# Generated by FakeRAM 2.0
VERSION 5.7 ;
BUSBITCHARS "[]" ;
PROPERTYDEFINITIONS
  MACRO width INTEGER ;
  MACRO depth INTEGER ;
  MACRO banks INTEGER ;
END PROPERTYDEFINITIONS
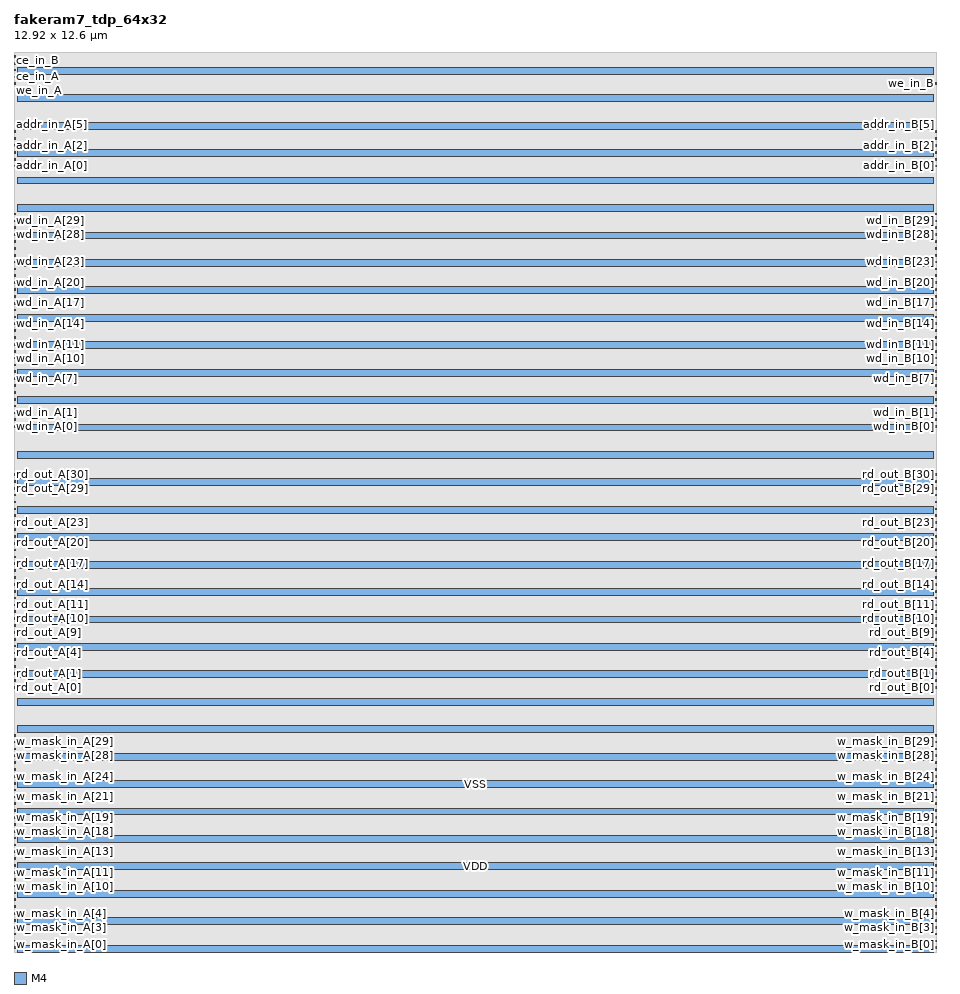
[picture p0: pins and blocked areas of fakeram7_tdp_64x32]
MACRO fakeram7_tdp_64x32
  PROPERTY width 32 ;
  PROPERTY depth 64 ;
  PROPERTY banks 2 ;
  FOREIGN fakeram7_tdp_64x32 0 0 ;
  SYMMETRY X Y ;
  SIZE 12.920 BY 12.600 ;
  CLASS BLOCK ;
  PIN w_mask_in_A[0]
    DIRECTION INPUT ;
    USE SIGNAL ;
    SHAPE ABUTMENT ;
    PORT
      LAYER M4 ;
      RECT 0.000 0.048 0.024 0.072 ;
    END
  END w_mask_in_A[0]
  PIN w_mask_in_B[0]
    DIRECTION INPUT ;
    USE SIGNAL ;
    SHAPE ABUTMENT ;
    PORT
      LAYER M4 ;
      RECT 12.896 0.048 12.920 0.072 ;
    END
  END w_mask_in_B[0]
  PIN w_mask_in_A[1]
    DIRECTION INPUT ;
    USE SIGNAL ;
    SHAPE ABUTMENT ;
    PORT
      LAYER M4 ;
      RECT 0.000 0.144 0.024 0.168 ;
    END
  END w_mask_in_A[1]
  PIN w_mask_in_B[1]
    DIRECTION INPUT ;
    USE SIGNAL ;
    SHAPE ABUTMENT ;
    PORT
      LAYER M4 ;
      RECT 12.896 0.144 12.920 0.168 ;
    END
  END w_mask_in_B[1]
  PIN w_mask_in_A[2]
    DIRECTION INPUT ;
    USE SIGNAL ;
    SHAPE ABUTMENT ;
    PORT
      LAYER M4 ;
      RECT 0.000 0.240 0.024 0.264 ;
    END
  END w_mask_in_A[2]
  PIN w_mask_in_B[2]
    DIRECTION INPUT ;
    USE SIGNAL ;
    SHAPE ABUTMENT ;
    PORT
      LAYER M4 ;
      RECT 12.896 0.240 12.920 0.264 ;
    END
  END w_mask_in_B[2]
  PIN w_mask_in_A[3]
    DIRECTION INPUT ;
    USE SIGNAL ;
    SHAPE ABUTMENT ;
    PORT
      LAYER M4 ;
      RECT 0.000 0.336 0.024 0.360 ;
    END
  END w_mask_in_A[3]
  PIN w_mask_in_B[3]
    DIRECTION INPUT ;
    USE SIGNAL ;
    SHAPE ABUTMENT ;
    PORT
      LAYER M4 ;
      RECT 12.896 0.336 12.920 0.360 ;
    END
  END w_mask_in_B[3]
  PIN w_mask_in_A[4]
    DIRECTION INPUT ;
    USE SIGNAL ;
    SHAPE ABUTMENT ;
    PORT
      LAYER M4 ;
      RECT 0.000 0.432 0.024 0.456 ;
    END
  END w_mask_in_A[4]
  PIN w_mask_in_B[4]
    DIRECTION INPUT ;
    USE SIGNAL ;
    SHAPE ABUTMENT ;
    PORT
      LAYER M4 ;
      RECT 12.896 0.432 12.920 0.456 ;
    END
  END w_mask_in_B[4]
  PIN w_mask_in_A[5]
    DIRECTION INPUT ;
    USE SIGNAL ;
    SHAPE ABUTMENT ;
    PORT
      LAYER M4 ;
      RECT 0.000 0.528 0.024 0.552 ;
    END
  END w_mask_in_A[5]
  PIN w_mask_in_B[5]
    DIRECTION INPUT ;
    USE SIGNAL ;
    SHAPE ABUTMENT ;
    PORT
      LAYER M4 ;
      RECT 12.896 0.528 12.920 0.552 ;
    END
  END w_mask_in_B[5]
  PIN w_mask_in_A[6]
    DIRECTION INPUT ;
    USE SIGNAL ;
    SHAPE ABUTMENT ;
    PORT
      LAYER M4 ;
      RECT 0.000 0.624 0.024 0.648 ;
    END
  END w_mask_in_A[6]
  PIN w_mask_in_B[6]
    DIRECTION INPUT ;
    USE SIGNAL ;
    SHAPE ABUTMENT ;
    PORT
      LAYER M4 ;
      RECT 12.896 0.624 12.920 0.648 ;
    END
  END w_mask_in_B[6]
  PIN w_mask_in_A[7]
    DIRECTION INPUT ;
    USE SIGNAL ;
    SHAPE ABUTMENT ;
    PORT
      LAYER M4 ;
      RECT 0.000 0.720 0.024 0.744 ;
    END
  END w_mask_in_A[7]
  PIN w_mask_in_B[7]
    DIRECTION INPUT ;
    USE SIGNAL ;
    SHAPE ABUTMENT ;
    PORT
      LAYER M4 ;
      RECT 12.896 0.720 12.920 0.744 ;
    END
  END w_mask_in_B[7]
  PIN w_mask_in_A[8]
    DIRECTION INPUT ;
    USE SIGNAL ;
    SHAPE ABUTMENT ;
    PORT
      LAYER M4 ;
      RECT 0.000 0.816 0.024 0.840 ;
    END
  END w_mask_in_A[8]
  PIN w_mask_in_B[8]
    DIRECTION INPUT ;
    USE SIGNAL ;
    SHAPE ABUTMENT ;
    PORT
      LAYER M4 ;
      RECT 12.896 0.816 12.920 0.840 ;
    END
  END w_mask_in_B[8]
  PIN w_mask_in_A[9]
    DIRECTION INPUT ;
    USE SIGNAL ;
    SHAPE ABUTMENT ;
    PORT
      LAYER M4 ;
      RECT 0.000 0.912 0.024 0.936 ;
    END
  END w_mask_in_A[9]
  PIN w_mask_in_B[9]
    DIRECTION INPUT ;
    USE SIGNAL ;
    SHAPE ABUTMENT ;
    PORT
      LAYER M4 ;
      RECT 12.896 0.912 12.920 0.936 ;
    END
  END w_mask_in_B[9]
  PIN w_mask_in_A[10]
    DIRECTION INPUT ;
    USE SIGNAL ;
    SHAPE ABUTMENT ;
    PORT
      LAYER M4 ;
      RECT 0.000 1.008 0.024 1.032 ;
    END
  END w_mask_in_A[10]
  PIN w_mask_in_B[10]
    DIRECTION INPUT ;
    USE SIGNAL ;
    SHAPE ABUTMENT ;
    PORT
      LAYER M4 ;
      RECT 12.896 1.008 12.920 1.032 ;
    END
  END w_mask_in_B[10]
  PIN w_mask_in_A[11]
    DIRECTION INPUT ;
    USE SIGNAL ;
    SHAPE ABUTMENT ;
    PORT
      LAYER M4 ;
      RECT 0.000 1.104 0.024 1.128 ;
    END
  END w_mask_in_A[11]
  PIN w_mask_in_B[11]
    DIRECTION INPUT ;
    USE SIGNAL ;
    SHAPE ABUTMENT ;
    PORT
      LAYER M4 ;
      RECT 12.896 1.104 12.920 1.128 ;
    END
  END w_mask_in_B[11]
  PIN w_mask_in_A[12]
    DIRECTION INPUT ;
    USE SIGNAL ;
    SHAPE ABUTMENT ;
    PORT
      LAYER M4 ;
      RECT 0.000 1.200 0.024 1.224 ;
    END
  END w_mask_in_A[12]
  PIN w_mask_in_B[12]
    DIRECTION INPUT ;
    USE SIGNAL ;
    SHAPE ABUTMENT ;
    PORT
      LAYER M4 ;
      RECT 12.896 1.200 12.920 1.224 ;
    END
  END w_mask_in_B[12]
  PIN w_mask_in_A[13]
    DIRECTION INPUT ;
    USE SIGNAL ;
    SHAPE ABUTMENT ;
    PORT
      LAYER M4 ;
      RECT 0.000 1.296 0.024 1.320 ;
    END
  END w_mask_in_A[13]
  PIN w_mask_in_B[13]
    DIRECTION INPUT ;
    USE SIGNAL ;
    SHAPE ABUTMENT ;
    PORT
      LAYER M4 ;
      RECT 12.896 1.296 12.920 1.320 ;
    END
  END w_mask_in_B[13]
  PIN w_mask_in_A[14]
    DIRECTION INPUT ;
    USE SIGNAL ;
    SHAPE ABUTMENT ;
    PORT
      LAYER M4 ;
      RECT 0.000 1.392 0.024 1.416 ;
    END
  END w_mask_in_A[14]
  PIN w_mask_in_B[14]
    DIRECTION INPUT ;
    USE SIGNAL ;
    SHAPE ABUTMENT ;
    PORT
      LAYER M4 ;
      RECT 12.896 1.392 12.920 1.416 ;
    END
  END w_mask_in_B[14]
  PIN w_mask_in_A[15]
    DIRECTION INPUT ;
    USE SIGNAL ;
    SHAPE ABUTMENT ;
    PORT
      LAYER M4 ;
      RECT 0.000 1.488 0.024 1.512 ;
    END
  END w_mask_in_A[15]
  PIN w_mask_in_B[15]
    DIRECTION INPUT ;
    USE SIGNAL ;
    SHAPE ABUTMENT ;
    PORT
      LAYER M4 ;
      RECT 12.896 1.488 12.920 1.512 ;
    END
  END w_mask_in_B[15]
  PIN w_mask_in_A[16]
    DIRECTION INPUT ;
    USE SIGNAL ;
    SHAPE ABUTMENT ;
    PORT
      LAYER M4 ;
      RECT 0.000 1.584 0.024 1.608 ;
    END
  END w_mask_in_A[16]
  PIN w_mask_in_B[16]
    DIRECTION INPUT ;
    USE SIGNAL ;
    SHAPE ABUTMENT ;
    PORT
      LAYER M4 ;
      RECT 12.896 1.584 12.920 1.608 ;
    END
  END w_mask_in_B[16]
  PIN w_mask_in_A[17]
    DIRECTION INPUT ;
    USE SIGNAL ;
    SHAPE ABUTMENT ;
    PORT
      LAYER M4 ;
      RECT 0.000 1.680 0.024 1.704 ;
    END
  END w_mask_in_A[17]
  PIN w_mask_in_B[17]
    DIRECTION INPUT ;
    USE SIGNAL ;
    SHAPE ABUTMENT ;
    PORT
      LAYER M4 ;
      RECT 12.896 1.680 12.920 1.704 ;
    END
  END w_mask_in_B[17]
  PIN w_mask_in_A[18]
    DIRECTION INPUT ;
    USE SIGNAL ;
    SHAPE ABUTMENT ;
    PORT
      LAYER M4 ;
      RECT 0.000 1.776 0.024 1.800 ;
    END
  END w_mask_in_A[18]
  PIN w_mask_in_B[18]
    DIRECTION INPUT ;
    USE SIGNAL ;
    SHAPE ABUTMENT ;
    PORT
      LAYER M4 ;
      RECT 12.896 1.776 12.920 1.800 ;
    END
  END w_mask_in_B[18]
  PIN w_mask_in_A[19]
    DIRECTION INPUT ;
    USE SIGNAL ;
    SHAPE ABUTMENT ;
    PORT
      LAYER M4 ;
      RECT 0.000 1.872 0.024 1.896 ;
    END
  END w_mask_in_A[19]
  PIN w_mask_in_B[19]
    DIRECTION INPUT ;
    USE SIGNAL ;
    SHAPE ABUTMENT ;
    PORT
      LAYER M4 ;
      RECT 12.896 1.872 12.920 1.896 ;
    END
  END w_mask_in_B[19]
  PIN w_mask_in_A[20]
    DIRECTION INPUT ;
    USE SIGNAL ;
    SHAPE ABUTMENT ;
    PORT
      LAYER M4 ;
      RECT 0.000 1.968 0.024 1.992 ;
    END
  END w_mask_in_A[20]
  PIN w_mask_in_B[20]
    DIRECTION INPUT ;
    USE SIGNAL ;
    SHAPE ABUTMENT ;
    PORT
      LAYER M4 ;
      RECT 12.896 1.968 12.920 1.992 ;
    END
  END w_mask_in_B[20]
  PIN w_mask_in_A[21]
    DIRECTION INPUT ;
    USE SIGNAL ;
    SHAPE ABUTMENT ;
    PORT
      LAYER M4 ;
      RECT 0.000 2.064 0.024 2.088 ;
    END
  END w_mask_in_A[21]
  PIN w_mask_in_B[21]
    DIRECTION INPUT ;
    USE SIGNAL ;
    SHAPE ABUTMENT ;
    PORT
      LAYER M4 ;
      RECT 12.896 2.064 12.920 2.088 ;
    END
  END w_mask_in_B[21]
  PIN w_mask_in_A[22]
    DIRECTION INPUT ;
    USE SIGNAL ;
    SHAPE ABUTMENT ;
    PORT
      LAYER M4 ;
      RECT 0.000 2.160 0.024 2.184 ;
    END
  END w_mask_in_A[22]
  PIN w_mask_in_B[22]
    DIRECTION INPUT ;
    USE SIGNAL ;
    SHAPE ABUTMENT ;
    PORT
      LAYER M4 ;
      RECT 12.896 2.160 12.920 2.184 ;
    END
  END w_mask_in_B[22]
  PIN w_mask_in_A[23]
    DIRECTION INPUT ;
    USE SIGNAL ;
    SHAPE ABUTMENT ;
    PORT
      LAYER M4 ;
      RECT 0.000 2.256 0.024 2.280 ;
    END
  END w_mask_in_A[23]
  PIN w_mask_in_B[23]
    DIRECTION INPUT ;
    USE SIGNAL ;
    SHAPE ABUTMENT ;
    PORT
      LAYER M4 ;
      RECT 12.896 2.256 12.920 2.280 ;
    END
  END w_mask_in_B[23]
  PIN w_mask_in_A[24]
    DIRECTION INPUT ;
    USE SIGNAL ;
    SHAPE ABUTMENT ;
    PORT
      LAYER M4 ;
      RECT 0.000 2.352 0.024 2.376 ;
    END
  END w_mask_in_A[24]
  PIN w_mask_in_B[24]
    DIRECTION INPUT ;
    USE SIGNAL ;
    SHAPE ABUTMENT ;
    PORT
      LAYER M4 ;
      RECT 12.896 2.352 12.920 2.376 ;
    END
  END w_mask_in_B[24]
  PIN w_mask_in_A[25]
    DIRECTION INPUT ;
    USE SIGNAL ;
    SHAPE ABUTMENT ;
    PORT
      LAYER M4 ;
      RECT 0.000 2.448 0.024 2.472 ;
    END
  END w_mask_in_A[25]
  PIN w_mask_in_B[25]
    DIRECTION INPUT ;
    USE SIGNAL ;
    SHAPE ABUTMENT ;
    PORT
      LAYER M4 ;
      RECT 12.896 2.448 12.920 2.472 ;
    END
  END w_mask_in_B[25]
  PIN w_mask_in_A[26]
    DIRECTION INPUT ;
    USE SIGNAL ;
    SHAPE ABUTMENT ;
    PORT
      LAYER M4 ;
      RECT 0.000 2.544 0.024 2.568 ;
    END
  END w_mask_in_A[26]
  PIN w_mask_in_B[26]
    DIRECTION INPUT ;
    USE SIGNAL ;
    SHAPE ABUTMENT ;
    PORT
      LAYER M4 ;
      RECT 12.896 2.544 12.920 2.568 ;
    END
  END w_mask_in_B[26]
  PIN w_mask_in_A[27]
    DIRECTION INPUT ;
    USE SIGNAL ;
    SHAPE ABUTMENT ;
    PORT
      LAYER M4 ;
      RECT 0.000 2.640 0.024 2.664 ;
    END
  END w_mask_in_A[27]
  PIN w_mask_in_B[27]
    DIRECTION INPUT ;
    USE SIGNAL ;
    SHAPE ABUTMENT ;
    PORT
      LAYER M4 ;
      RECT 12.896 2.640 12.920 2.664 ;
    END
  END w_mask_in_B[27]
  PIN w_mask_in_A[28]
    DIRECTION INPUT ;
    USE SIGNAL ;
    SHAPE ABUTMENT ;
    PORT
      LAYER M4 ;
      RECT 0.000 2.736 0.024 2.760 ;
    END
  END w_mask_in_A[28]
  PIN w_mask_in_B[28]
    DIRECTION INPUT ;
    USE SIGNAL ;
    SHAPE ABUTMENT ;
    PORT
      LAYER M4 ;
      RECT 12.896 2.736 12.920 2.760 ;
    END
  END w_mask_in_B[28]
  PIN w_mask_in_A[29]
    DIRECTION INPUT ;
    USE SIGNAL ;
    SHAPE ABUTMENT ;
    PORT
      LAYER M4 ;
      RECT 0.000 2.832 0.024 2.856 ;
    END
  END w_mask_in_A[29]
  PIN w_mask_in_B[29]
    DIRECTION INPUT ;
    USE SIGNAL ;
    SHAPE ABUTMENT ;
    PORT
      LAYER M4 ;
      RECT 12.896 2.832 12.920 2.856 ;
    END
  END w_mask_in_B[29]
  PIN w_mask_in_A[30]
    DIRECTION INPUT ;
    USE SIGNAL ;
    SHAPE ABUTMENT ;
    PORT
      LAYER M4 ;
      RECT 0.000 2.928 0.024 2.952 ;
    END
  END w_mask_in_A[30]
  PIN w_mask_in_B[30]
    DIRECTION INPUT ;
    USE SIGNAL ;
    SHAPE ABUTMENT ;
    PORT
      LAYER M4 ;
      RECT 12.896 2.928 12.920 2.952 ;
    END
  END w_mask_in_B[30]
  PIN w_mask_in_A[31]
    DIRECTION INPUT ;
    USE SIGNAL ;
    SHAPE ABUTMENT ;
    PORT
      LAYER M4 ;
      RECT 0.000 3.024 0.024 3.048 ;
    END
  END w_mask_in_A[31]
  PIN w_mask_in_B[31]
    DIRECTION INPUT ;
    USE SIGNAL ;
    SHAPE ABUTMENT ;
    PORT
      LAYER M4 ;
      RECT 12.896 3.024 12.920 3.048 ;
    END
  END w_mask_in_B[31]
  PIN rd_out_A[0]
    DIRECTION OUTPUT ;
    USE SIGNAL ;
    SHAPE ABUTMENT ;
    PORT
      LAYER M4 ;
      RECT 0.000 3.696 0.024 3.720 ;
    END
  END rd_out_A[0]
  PIN rd_out_B[0]
    DIRECTION OUTPUT ;
    USE SIGNAL ;
    SHAPE ABUTMENT ;
    PORT
      LAYER M4 ;
      RECT 12.896 3.696 12.920 3.720 ;
    END
  END rd_out_B[0]
  PIN rd_out_A[1]
    DIRECTION OUTPUT ;
    USE SIGNAL ;
    SHAPE ABUTMENT ;
    PORT
      LAYER M4 ;
      RECT 0.000 3.792 0.024 3.816 ;
    END
  END rd_out_A[1]
  PIN rd_out_B[1]
    DIRECTION OUTPUT ;
    USE SIGNAL ;
    SHAPE ABUTMENT ;
    PORT
      LAYER M4 ;
      RECT 12.896 3.792 12.920 3.816 ;
    END
  END rd_out_B[1]
  PIN rd_out_A[2]
    DIRECTION OUTPUT ;
    USE SIGNAL ;
    SHAPE ABUTMENT ;
    PORT
      LAYER M4 ;
      RECT 0.000 3.888 0.024 3.912 ;
    END
  END rd_out_A[2]
  PIN rd_out_B[2]
    DIRECTION OUTPUT ;
    USE SIGNAL ;
    SHAPE ABUTMENT ;
    PORT
      LAYER M4 ;
      RECT 12.896 3.888 12.920 3.912 ;
    END
  END rd_out_B[2]
  PIN rd_out_A[3]
    DIRECTION OUTPUT ;
    USE SIGNAL ;
    SHAPE ABUTMENT ;
    PORT
      LAYER M4 ;
      RECT 0.000 3.984 0.024 4.008 ;
    END
  END rd_out_A[3]
  PIN rd_out_B[3]
    DIRECTION OUTPUT ;
    USE SIGNAL ;
    SHAPE ABUTMENT ;
    PORT
      LAYER M4 ;
      RECT 12.896 3.984 12.920 4.008 ;
    END
  END rd_out_B[3]
  PIN rd_out_A[4]
    DIRECTION OUTPUT ;
    USE SIGNAL ;
    SHAPE ABUTMENT ;
    PORT
      LAYER M4 ;
      RECT 0.000 4.080 0.024 4.104 ;
    END
  END rd_out_A[4]
  PIN rd_out_B[4]
    DIRECTION OUTPUT ;
    USE SIGNAL ;
    SHAPE ABUTMENT ;
    PORT
      LAYER M4 ;
      RECT 12.896 4.080 12.920 4.104 ;
    END
  END rd_out_B[4]
  PIN rd_out_A[5]
    DIRECTION OUTPUT ;
    USE SIGNAL ;
    SHAPE ABUTMENT ;
    PORT
      LAYER M4 ;
      RECT 0.000 4.176 0.024 4.200 ;
    END
  END rd_out_A[5]
  PIN rd_out_B[5]
    DIRECTION OUTPUT ;
    USE SIGNAL ;
    SHAPE ABUTMENT ;
    PORT
      LAYER M4 ;
      RECT 12.896 4.176 12.920 4.200 ;
    END
  END rd_out_B[5]
  PIN rd_out_A[6]
    DIRECTION OUTPUT ;
    USE SIGNAL ;
    SHAPE ABUTMENT ;
    PORT
      LAYER M4 ;
      RECT 0.000 4.272 0.024 4.296 ;
    END
  END rd_out_A[6]
  PIN rd_out_B[6]
    DIRECTION OUTPUT ;
    USE SIGNAL ;
    SHAPE ABUTMENT ;
    PORT
      LAYER M4 ;
      RECT 12.896 4.272 12.920 4.296 ;
    END
  END rd_out_B[6]
  PIN rd_out_A[7]
    DIRECTION OUTPUT ;
    USE SIGNAL ;
    SHAPE ABUTMENT ;
    PORT
      LAYER M4 ;
      RECT 0.000 4.368 0.024 4.392 ;
    END
  END rd_out_A[7]
  PIN rd_out_B[7]
    DIRECTION OUTPUT ;
    USE SIGNAL ;
    SHAPE ABUTMENT ;
    PORT
      LAYER M4 ;
      RECT 12.896 4.368 12.920 4.392 ;
    END
  END rd_out_B[7]
  PIN rd_out_A[8]
    DIRECTION OUTPUT ;
    USE SIGNAL ;
    SHAPE ABUTMENT ;
    PORT
      LAYER M4 ;
      RECT 0.000 4.464 0.024 4.488 ;
    END
  END rd_out_A[8]
  PIN rd_out_B[8]
    DIRECTION OUTPUT ;
    USE SIGNAL ;
    SHAPE ABUTMENT ;
    PORT
      LAYER M4 ;
      RECT 12.896 4.464 12.920 4.488 ;
    END
  END rd_out_B[8]
  PIN rd_out_A[9]
    DIRECTION OUTPUT ;
    USE SIGNAL ;
    SHAPE ABUTMENT ;
    PORT
      LAYER M4 ;
      RECT 0.000 4.560 0.024 4.584 ;
    END
  END rd_out_A[9]
  PIN rd_out_B[9]
    DIRECTION OUTPUT ;
    USE SIGNAL ;
    SHAPE ABUTMENT ;
    PORT
      LAYER M4 ;
      RECT 12.896 4.560 12.920 4.584 ;
    END
  END rd_out_B[9]
  PIN rd_out_A[10]
    DIRECTION OUTPUT ;
    USE SIGNAL ;
    SHAPE ABUTMENT ;
    PORT
      LAYER M4 ;
      RECT 0.000 4.656 0.024 4.680 ;
    END
  END rd_out_A[10]
  PIN rd_out_B[10]
    DIRECTION OUTPUT ;
    USE SIGNAL ;
    SHAPE ABUTMENT ;
    PORT
      LAYER M4 ;
      RECT 12.896 4.656 12.920 4.680 ;
    END
  END rd_out_B[10]
  PIN rd_out_A[11]
    DIRECTION OUTPUT ;
    USE SIGNAL ;
    SHAPE ABUTMENT ;
    PORT
      LAYER M4 ;
      RECT 0.000 4.752 0.024 4.776 ;
    END
  END rd_out_A[11]
  PIN rd_out_B[11]
    DIRECTION OUTPUT ;
    USE SIGNAL ;
    SHAPE ABUTMENT ;
    PORT
      LAYER M4 ;
      RECT 12.896 4.752 12.920 4.776 ;
    END
  END rd_out_B[11]
  PIN rd_out_A[12]
    DIRECTION OUTPUT ;
    USE SIGNAL ;
    SHAPE ABUTMENT ;
    PORT
      LAYER M4 ;
      RECT 0.000 4.848 0.024 4.872 ;
    END
  END rd_out_A[12]
  PIN rd_out_B[12]
    DIRECTION OUTPUT ;
    USE SIGNAL ;
    SHAPE ABUTMENT ;
    PORT
      LAYER M4 ;
      RECT 12.896 4.848 12.920 4.872 ;
    END
  END rd_out_B[12]
  PIN rd_out_A[13]
    DIRECTION OUTPUT ;
    USE SIGNAL ;
    SHAPE ABUTMENT ;
    PORT
      LAYER M4 ;
      RECT 0.000 4.944 0.024 4.968 ;
    END
  END rd_out_A[13]
  PIN rd_out_B[13]
    DIRECTION OUTPUT ;
    USE SIGNAL ;
    SHAPE ABUTMENT ;
    PORT
      LAYER M4 ;
      RECT 12.896 4.944 12.920 4.968 ;
    END
  END rd_out_B[13]
  PIN rd_out_A[14]
    DIRECTION OUTPUT ;
    USE SIGNAL ;
    SHAPE ABUTMENT ;
    PORT
      LAYER M4 ;
      RECT 0.000 5.040 0.024 5.064 ;
    END
  END rd_out_A[14]
  PIN rd_out_B[14]
    DIRECTION OUTPUT ;
    USE SIGNAL ;
    SHAPE ABUTMENT ;
    PORT
      LAYER M4 ;
      RECT 12.896 5.040 12.920 5.064 ;
    END
  END rd_out_B[14]
  PIN rd_out_A[15]
    DIRECTION OUTPUT ;
    USE SIGNAL ;
    SHAPE ABUTMENT ;
    PORT
      LAYER M4 ;
      RECT 0.000 5.136 0.024 5.160 ;
    END
  END rd_out_A[15]
  PIN rd_out_B[15]
    DIRECTION OUTPUT ;
    USE SIGNAL ;
    SHAPE ABUTMENT ;
    PORT
      LAYER M4 ;
      RECT 12.896 5.136 12.920 5.160 ;
    END
  END rd_out_B[15]
  PIN rd_out_A[16]
    DIRECTION OUTPUT ;
    USE SIGNAL ;
    SHAPE ABUTMENT ;
    PORT
      LAYER M4 ;
      RECT 0.000 5.232 0.024 5.256 ;
    END
  END rd_out_A[16]
  PIN rd_out_B[16]
    DIRECTION OUTPUT ;
    USE SIGNAL ;
    SHAPE ABUTMENT ;
    PORT
      LAYER M4 ;
      RECT 12.896 5.232 12.920 5.256 ;
    END
  END rd_out_B[16]
  PIN rd_out_A[17]
    DIRECTION OUTPUT ;
    USE SIGNAL ;
    SHAPE ABUTMENT ;
    PORT
      LAYER M4 ;
      RECT 0.000 5.328 0.024 5.352 ;
    END
  END rd_out_A[17]
  PIN rd_out_B[17]
    DIRECTION OUTPUT ;
    USE SIGNAL ;
    SHAPE ABUTMENT ;
    PORT
      LAYER M4 ;
      RECT 12.896 5.328 12.920 5.352 ;
    END
  END rd_out_B[17]
  PIN rd_out_A[18]
    DIRECTION OUTPUT ;
    USE SIGNAL ;
    SHAPE ABUTMENT ;
    PORT
      LAYER M4 ;
      RECT 0.000 5.424 0.024 5.448 ;
    END
  END rd_out_A[18]
  PIN rd_out_B[18]
    DIRECTION OUTPUT ;
    USE SIGNAL ;
    SHAPE ABUTMENT ;
    PORT
      LAYER M4 ;
      RECT 12.896 5.424 12.920 5.448 ;
    END
  END rd_out_B[18]
  PIN rd_out_A[19]
    DIRECTION OUTPUT ;
    USE SIGNAL ;
    SHAPE ABUTMENT ;
    PORT
      LAYER M4 ;
      RECT 0.000 5.520 0.024 5.544 ;
    END
  END rd_out_A[19]
  PIN rd_out_B[19]
    DIRECTION OUTPUT ;
    USE SIGNAL ;
    SHAPE ABUTMENT ;
    PORT
      LAYER M4 ;
      RECT 12.896 5.520 12.920 5.544 ;
    END
  END rd_out_B[19]
  PIN rd_out_A[20]
    DIRECTION OUTPUT ;
    USE SIGNAL ;
    SHAPE ABUTMENT ;
    PORT
      LAYER M4 ;
      RECT 0.000 5.616 0.024 5.640 ;
    END
  END rd_out_A[20]
  PIN rd_out_B[20]
    DIRECTION OUTPUT ;
    USE SIGNAL ;
    SHAPE ABUTMENT ;
    PORT
      LAYER M4 ;
      RECT 12.896 5.616 12.920 5.640 ;
    END
  END rd_out_B[20]
  PIN rd_out_A[21]
    DIRECTION OUTPUT ;
    USE SIGNAL ;
    SHAPE ABUTMENT ;
    PORT
      LAYER M4 ;
      RECT 0.000 5.712 0.024 5.736 ;
    END
  END rd_out_A[21]
  PIN rd_out_B[21]
    DIRECTION OUTPUT ;
    USE SIGNAL ;
    SHAPE ABUTMENT ;
    PORT
      LAYER M4 ;
      RECT 12.896 5.712 12.920 5.736 ;
    END
  END rd_out_B[21]
  PIN rd_out_A[22]
    DIRECTION OUTPUT ;
    USE SIGNAL ;
    SHAPE ABUTMENT ;
    PORT
      LAYER M4 ;
      RECT 0.000 5.808 0.024 5.832 ;
    END
  END rd_out_A[22]
  PIN rd_out_B[22]
    DIRECTION OUTPUT ;
    USE SIGNAL ;
    SHAPE ABUTMENT ;
    PORT
      LAYER M4 ;
      RECT 12.896 5.808 12.920 5.832 ;
    END
  END rd_out_B[22]
  PIN rd_out_A[23]
    DIRECTION OUTPUT ;
    USE SIGNAL ;
    SHAPE ABUTMENT ;
    PORT
      LAYER M4 ;
      RECT 0.000 5.904 0.024 5.928 ;
    END
  END rd_out_A[23]
  PIN rd_out_B[23]
    DIRECTION OUTPUT ;
    USE SIGNAL ;
    SHAPE ABUTMENT ;
    PORT
      LAYER M4 ;
      RECT 12.896 5.904 12.920 5.928 ;
    END
  END rd_out_B[23]
  PIN rd_out_A[24]
    DIRECTION OUTPUT ;
    USE SIGNAL ;
    SHAPE ABUTMENT ;
    PORT
      LAYER M4 ;
      RECT 0.000 6.000 0.024 6.024 ;
    END
  END rd_out_A[24]
  PIN rd_out_B[24]
    DIRECTION OUTPUT ;
    USE SIGNAL ;
    SHAPE ABUTMENT ;
    PORT
      LAYER M4 ;
      RECT 12.896 6.000 12.920 6.024 ;
    END
  END rd_out_B[24]
  PIN rd_out_A[25]
    DIRECTION OUTPUT ;
    USE SIGNAL ;
    SHAPE ABUTMENT ;
    PORT
      LAYER M4 ;
      RECT 0.000 6.096 0.024 6.120 ;
    END
  END rd_out_A[25]
  PIN rd_out_B[25]
    DIRECTION OUTPUT ;
    USE SIGNAL ;
    SHAPE ABUTMENT ;
    PORT
      LAYER M4 ;
      RECT 12.896 6.096 12.920 6.120 ;
    END
  END rd_out_B[25]
  PIN rd_out_A[26]
    DIRECTION OUTPUT ;
    USE SIGNAL ;
    SHAPE ABUTMENT ;
    PORT
      LAYER M4 ;
      RECT 0.000 6.192 0.024 6.216 ;
    END
  END rd_out_A[26]
  PIN rd_out_B[26]
    DIRECTION OUTPUT ;
    USE SIGNAL ;
    SHAPE ABUTMENT ;
    PORT
      LAYER M4 ;
      RECT 12.896 6.192 12.920 6.216 ;
    END
  END rd_out_B[26]
  PIN rd_out_A[27]
    DIRECTION OUTPUT ;
    USE SIGNAL ;
    SHAPE ABUTMENT ;
    PORT
      LAYER M4 ;
      RECT 0.000 6.288 0.024 6.312 ;
    END
  END rd_out_A[27]
  PIN rd_out_B[27]
    DIRECTION OUTPUT ;
    USE SIGNAL ;
    SHAPE ABUTMENT ;
    PORT
      LAYER M4 ;
      RECT 12.896 6.288 12.920 6.312 ;
    END
  END rd_out_B[27]
  PIN rd_out_A[28]
    DIRECTION OUTPUT ;
    USE SIGNAL ;
    SHAPE ABUTMENT ;
    PORT
      LAYER M4 ;
      RECT 0.000 6.384 0.024 6.408 ;
    END
  END rd_out_A[28]
  PIN rd_out_B[28]
    DIRECTION OUTPUT ;
    USE SIGNAL ;
    SHAPE ABUTMENT ;
    PORT
      LAYER M4 ;
      RECT 12.896 6.384 12.920 6.408 ;
    END
  END rd_out_B[28]
  PIN rd_out_A[29]
    DIRECTION OUTPUT ;
    USE SIGNAL ;
    SHAPE ABUTMENT ;
    PORT
      LAYER M4 ;
      RECT 0.000 6.480 0.024 6.504 ;
    END
  END rd_out_A[29]
  PIN rd_out_B[29]
    DIRECTION OUTPUT ;
    USE SIGNAL ;
    SHAPE ABUTMENT ;
    PORT
      LAYER M4 ;
      RECT 12.896 6.480 12.920 6.504 ;
    END
  END rd_out_B[29]
  PIN rd_out_A[30]
    DIRECTION OUTPUT ;
    USE SIGNAL ;
    SHAPE ABUTMENT ;
    PORT
      LAYER M4 ;
      RECT 0.000 6.576 0.024 6.600 ;
    END
  END rd_out_A[30]
  PIN rd_out_B[30]
    DIRECTION OUTPUT ;
    USE SIGNAL ;
    SHAPE ABUTMENT ;
    PORT
      LAYER M4 ;
      RECT 12.896 6.576 12.920 6.600 ;
    END
  END rd_out_B[30]
  PIN rd_out_A[31]
    DIRECTION OUTPUT ;
    USE SIGNAL ;
    SHAPE ABUTMENT ;
    PORT
      LAYER M4 ;
      RECT 0.000 6.672 0.024 6.696 ;
    END
  END rd_out_A[31]
  PIN rd_out_B[31]
    DIRECTION OUTPUT ;
    USE SIGNAL ;
    SHAPE ABUTMENT ;
    PORT
      LAYER M4 ;
      RECT 12.896 6.672 12.920 6.696 ;
    END
  END rd_out_B[31]
  PIN wd_in_A[0]
    DIRECTION INPUT ;
    USE SIGNAL ;
    SHAPE ABUTMENT ;
    PORT
      LAYER M4 ;
      RECT 0.000 7.344 0.024 7.368 ;
    END
  END wd_in_A[0]
  PIN wd_in_B[0]
    DIRECTION INPUT ;
    USE SIGNAL ;
    SHAPE ABUTMENT ;
    PORT
      LAYER M4 ;
      RECT 12.896 7.344 12.920 7.368 ;
    END
  END wd_in_B[0]
  PIN wd_in_A[1]
    DIRECTION INPUT ;
    USE SIGNAL ;
    SHAPE ABUTMENT ;
    PORT
      LAYER M4 ;
      RECT 0.000 7.440 0.024 7.464 ;
    END
  END wd_in_A[1]
  PIN wd_in_B[1]
    DIRECTION INPUT ;
    USE SIGNAL ;
    SHAPE ABUTMENT ;
    PORT
      LAYER M4 ;
      RECT 12.896 7.440 12.920 7.464 ;
    END
  END wd_in_B[1]
  PIN wd_in_A[2]
    DIRECTION INPUT ;
    USE SIGNAL ;
    SHAPE ABUTMENT ;
    PORT
      LAYER M4 ;
      RECT 0.000 7.536 0.024 7.560 ;
    END
  END wd_in_A[2]
  PIN wd_in_B[2]
    DIRECTION INPUT ;
    USE SIGNAL ;
    SHAPE ABUTMENT ;
    PORT
      LAYER M4 ;
      RECT 12.896 7.536 12.920 7.560 ;
    END
  END wd_in_B[2]
  PIN wd_in_A[3]
    DIRECTION INPUT ;
    USE SIGNAL ;
    SHAPE ABUTMENT ;
    PORT
      LAYER M4 ;
      RECT 0.000 7.632 0.024 7.656 ;
    END
  END wd_in_A[3]
  PIN wd_in_B[3]
    DIRECTION INPUT ;
    USE SIGNAL ;
    SHAPE ABUTMENT ;
    PORT
      LAYER M4 ;
      RECT 12.896 7.632 12.920 7.656 ;
    END
  END wd_in_B[3]
  PIN wd_in_A[4]
    DIRECTION INPUT ;
    USE SIGNAL ;
    SHAPE ABUTMENT ;
    PORT
      LAYER M4 ;
      RECT 0.000 7.728 0.024 7.752 ;
    END
  END wd_in_A[4]
  PIN wd_in_B[4]
    DIRECTION INPUT ;
    USE SIGNAL ;
    SHAPE ABUTMENT ;
    PORT
      LAYER M4 ;
      RECT 12.896 7.728 12.920 7.752 ;
    END
  END wd_in_B[4]
  PIN wd_in_A[5]
    DIRECTION INPUT ;
    USE SIGNAL ;
    SHAPE ABUTMENT ;
    PORT
      LAYER M4 ;
      RECT 0.000 7.824 0.024 7.848 ;
    END
  END wd_in_A[5]
  PIN wd_in_B[5]
    DIRECTION INPUT ;
    USE SIGNAL ;
    SHAPE ABUTMENT ;
    PORT
      LAYER M4 ;
      RECT 12.896 7.824 12.920 7.848 ;
    END
  END wd_in_B[5]
  PIN wd_in_A[6]
    DIRECTION INPUT ;
    USE SIGNAL ;
    SHAPE ABUTMENT ;
    PORT
      LAYER M4 ;
      RECT 0.000 7.920 0.024 7.944 ;
    END
  END wd_in_A[6]
  PIN wd_in_B[6]
    DIRECTION INPUT ;
    USE SIGNAL ;
    SHAPE ABUTMENT ;
    PORT
      LAYER M4 ;
      RECT 12.896 7.920 12.920 7.944 ;
    END
  END wd_in_B[6]
  PIN wd_in_A[7]
    DIRECTION INPUT ;
    USE SIGNAL ;
    SHAPE ABUTMENT ;
    PORT
      LAYER M4 ;
      RECT 0.000 8.016 0.024 8.040 ;
    END
  END wd_in_A[7]
  PIN wd_in_B[7]
    DIRECTION INPUT ;
    USE SIGNAL ;
    SHAPE ABUTMENT ;
    PORT
      LAYER M4 ;
      RECT 12.896 8.016 12.920 8.040 ;
    END
  END wd_in_B[7]
  PIN wd_in_A[8]
    DIRECTION INPUT ;
    USE SIGNAL ;
    SHAPE ABUTMENT ;
    PORT
      LAYER M4 ;
      RECT 0.000 8.112 0.024 8.136 ;
    END
  END wd_in_A[8]
  PIN wd_in_B[8]
    DIRECTION INPUT ;
    USE SIGNAL ;
    SHAPE ABUTMENT ;
    PORT
      LAYER M4 ;
      RECT 12.896 8.112 12.920 8.136 ;
    END
  END wd_in_B[8]
  PIN wd_in_A[9]
    DIRECTION INPUT ;
    USE SIGNAL ;
    SHAPE ABUTMENT ;
    PORT
      LAYER M4 ;
      RECT 0.000 8.208 0.024 8.232 ;
    END
  END wd_in_A[9]
  PIN wd_in_B[9]
    DIRECTION INPUT ;
    USE SIGNAL ;
    SHAPE ABUTMENT ;
    PORT
      LAYER M4 ;
      RECT 12.896 8.208 12.920 8.232 ;
    END
  END wd_in_B[9]
  PIN wd_in_A[10]
    DIRECTION INPUT ;
    USE SIGNAL ;
    SHAPE ABUTMENT ;
    PORT
      LAYER M4 ;
      RECT 0.000 8.304 0.024 8.328 ;
    END
  END wd_in_A[10]
  PIN wd_in_B[10]
    DIRECTION INPUT ;
    USE SIGNAL ;
    SHAPE ABUTMENT ;
    PORT
      LAYER M4 ;
      RECT 12.896 8.304 12.920 8.328 ;
    END
  END wd_in_B[10]
  PIN wd_in_A[11]
    DIRECTION INPUT ;
    USE SIGNAL ;
    SHAPE ABUTMENT ;
    PORT
      LAYER M4 ;
      RECT 0.000 8.400 0.024 8.424 ;
    END
  END wd_in_A[11]
  PIN wd_in_B[11]
    DIRECTION INPUT ;
    USE SIGNAL ;
    SHAPE ABUTMENT ;
    PORT
      LAYER M4 ;
      RECT 12.896 8.400 12.920 8.424 ;
    END
  END wd_in_B[11]
  PIN wd_in_A[12]
    DIRECTION INPUT ;
    USE SIGNAL ;
    SHAPE ABUTMENT ;
    PORT
      LAYER M4 ;
      RECT 0.000 8.496 0.024 8.520 ;
    END
  END wd_in_A[12]
  PIN wd_in_B[12]
    DIRECTION INPUT ;
    USE SIGNAL ;
    SHAPE ABUTMENT ;
    PORT
      LAYER M4 ;
      RECT 12.896 8.496 12.920 8.520 ;
    END
  END wd_in_B[12]
  PIN wd_in_A[13]
    DIRECTION INPUT ;
    USE SIGNAL ;
    SHAPE ABUTMENT ;
    PORT
      LAYER M4 ;
      RECT 0.000 8.592 0.024 8.616 ;
    END
  END wd_in_A[13]
  PIN wd_in_B[13]
    DIRECTION INPUT ;
    USE SIGNAL ;
    SHAPE ABUTMENT ;
    PORT
      LAYER M4 ;
      RECT 12.896 8.592 12.920 8.616 ;
    END
  END wd_in_B[13]
  PIN wd_in_A[14]
    DIRECTION INPUT ;
    USE SIGNAL ;
    SHAPE ABUTMENT ;
    PORT
      LAYER M4 ;
      RECT 0.000 8.688 0.024 8.712 ;
    END
  END wd_in_A[14]
  PIN wd_in_B[14]
    DIRECTION INPUT ;
    USE SIGNAL ;
    SHAPE ABUTMENT ;
    PORT
      LAYER M4 ;
      RECT 12.896 8.688 12.920 8.712 ;
    END
  END wd_in_B[14]
  PIN wd_in_A[15]
    DIRECTION INPUT ;
    USE SIGNAL ;
    SHAPE ABUTMENT ;
    PORT
      LAYER M4 ;
      RECT 0.000 8.784 0.024 8.808 ;
    END
  END wd_in_A[15]
  PIN wd_in_B[15]
    DIRECTION INPUT ;
    USE SIGNAL ;
    SHAPE ABUTMENT ;
    PORT
      LAYER M4 ;
      RECT 12.896 8.784 12.920 8.808 ;
    END
  END wd_in_B[15]
  PIN wd_in_A[16]
    DIRECTION INPUT ;
    USE SIGNAL ;
    SHAPE ABUTMENT ;
    PORT
      LAYER M4 ;
      RECT 0.000 8.880 0.024 8.904 ;
    END
  END wd_in_A[16]
  PIN wd_in_B[16]
    DIRECTION INPUT ;
    USE SIGNAL ;
    SHAPE ABUTMENT ;
    PORT
      LAYER M4 ;
      RECT 12.896 8.880 12.920 8.904 ;
    END
  END wd_in_B[16]
  PIN wd_in_A[17]
    DIRECTION INPUT ;
    USE SIGNAL ;
    SHAPE ABUTMENT ;
    PORT
      LAYER M4 ;
      RECT 0.000 8.976 0.024 9.000 ;
    END
  END wd_in_A[17]
  PIN wd_in_B[17]
    DIRECTION INPUT ;
    USE SIGNAL ;
    SHAPE ABUTMENT ;
    PORT
      LAYER M4 ;
      RECT 12.896 8.976 12.920 9.000 ;
    END
  END wd_in_B[17]
  PIN wd_in_A[18]
    DIRECTION INPUT ;
    USE SIGNAL ;
    SHAPE ABUTMENT ;
    PORT
      LAYER M4 ;
      RECT 0.000 9.072 0.024 9.096 ;
    END
  END wd_in_A[18]
  PIN wd_in_B[18]
    DIRECTION INPUT ;
    USE SIGNAL ;
    SHAPE ABUTMENT ;
    PORT
      LAYER M4 ;
      RECT 12.896 9.072 12.920 9.096 ;
    END
  END wd_in_B[18]
  PIN wd_in_A[19]
    DIRECTION INPUT ;
    USE SIGNAL ;
    SHAPE ABUTMENT ;
    PORT
      LAYER M4 ;
      RECT 0.000 9.168 0.024 9.192 ;
    END
  END wd_in_A[19]
  PIN wd_in_B[19]
    DIRECTION INPUT ;
    USE SIGNAL ;
    SHAPE ABUTMENT ;
    PORT
      LAYER M4 ;
      RECT 12.896 9.168 12.920 9.192 ;
    END
  END wd_in_B[19]
  PIN wd_in_A[20]
    DIRECTION INPUT ;
    USE SIGNAL ;
    SHAPE ABUTMENT ;
    PORT
      LAYER M4 ;
      RECT 0.000 9.264 0.024 9.288 ;
    END
  END wd_in_A[20]
  PIN wd_in_B[20]
    DIRECTION INPUT ;
    USE SIGNAL ;
    SHAPE ABUTMENT ;
    PORT
      LAYER M4 ;
      RECT 12.896 9.264 12.920 9.288 ;
    END
  END wd_in_B[20]
  PIN wd_in_A[21]
    DIRECTION INPUT ;
    USE SIGNAL ;
    SHAPE ABUTMENT ;
    PORT
      LAYER M4 ;
      RECT 0.000 9.360 0.024 9.384 ;
    END
  END wd_in_A[21]
  PIN wd_in_B[21]
    DIRECTION INPUT ;
    USE SIGNAL ;
    SHAPE ABUTMENT ;
    PORT
      LAYER M4 ;
      RECT 12.896 9.360 12.920 9.384 ;
    END
  END wd_in_B[21]
  PIN wd_in_A[22]
    DIRECTION INPUT ;
    USE SIGNAL ;
    SHAPE ABUTMENT ;
    PORT
      LAYER M4 ;
      RECT 0.000 9.456 0.024 9.480 ;
    END
  END wd_in_A[22]
  PIN wd_in_B[22]
    DIRECTION INPUT ;
    USE SIGNAL ;
    SHAPE ABUTMENT ;
    PORT
      LAYER M4 ;
      RECT 12.896 9.456 12.920 9.480 ;
    END
  END wd_in_B[22]
  PIN wd_in_A[23]
    DIRECTION INPUT ;
    USE SIGNAL ;
    SHAPE ABUTMENT ;
    PORT
      LAYER M4 ;
      RECT 0.000 9.552 0.024 9.576 ;
    END
  END wd_in_A[23]
  PIN wd_in_B[23]
    DIRECTION INPUT ;
    USE SIGNAL ;
    SHAPE ABUTMENT ;
    PORT
      LAYER M4 ;
      RECT 12.896 9.552 12.920 9.576 ;
    END
  END wd_in_B[23]
  PIN wd_in_A[24]
    DIRECTION INPUT ;
    USE SIGNAL ;
    SHAPE ABUTMENT ;
    PORT
      LAYER M4 ;
      RECT 0.000 9.648 0.024 9.672 ;
    END
  END wd_in_A[24]
  PIN wd_in_B[24]
    DIRECTION INPUT ;
    USE SIGNAL ;
    SHAPE ABUTMENT ;
    PORT
      LAYER M4 ;
      RECT 12.896 9.648 12.920 9.672 ;
    END
  END wd_in_B[24]
  PIN wd_in_A[25]
    DIRECTION INPUT ;
    USE SIGNAL ;
    SHAPE ABUTMENT ;
    PORT
      LAYER M4 ;
      RECT 0.000 9.744 0.024 9.768 ;
    END
  END wd_in_A[25]
  PIN wd_in_B[25]
    DIRECTION INPUT ;
    USE SIGNAL ;
    SHAPE ABUTMENT ;
    PORT
      LAYER M4 ;
      RECT 12.896 9.744 12.920 9.768 ;
    END
  END wd_in_B[25]
  PIN wd_in_A[26]
    DIRECTION INPUT ;
    USE SIGNAL ;
    SHAPE ABUTMENT ;
    PORT
      LAYER M4 ;
      RECT 0.000 9.840 0.024 9.864 ;
    END
  END wd_in_A[26]
  PIN wd_in_B[26]
    DIRECTION INPUT ;
    USE SIGNAL ;
    SHAPE ABUTMENT ;
    PORT
      LAYER M4 ;
      RECT 12.896 9.840 12.920 9.864 ;
    END
  END wd_in_B[26]
  PIN wd_in_A[27]
    DIRECTION INPUT ;
    USE SIGNAL ;
    SHAPE ABUTMENT ;
    PORT
      LAYER M4 ;
      RECT 0.000 9.936 0.024 9.960 ;
    END
  END wd_in_A[27]
  PIN wd_in_B[27]
    DIRECTION INPUT ;
    USE SIGNAL ;
    SHAPE ABUTMENT ;
    PORT
      LAYER M4 ;
      RECT 12.896 9.936 12.920 9.960 ;
    END
  END wd_in_B[27]
  PIN wd_in_A[28]
    DIRECTION INPUT ;
    USE SIGNAL ;
    SHAPE ABUTMENT ;
    PORT
      LAYER M4 ;
      RECT 0.000 10.032 0.024 10.056 ;
    END
  END wd_in_A[28]
  PIN wd_in_B[28]
    DIRECTION INPUT ;
    USE SIGNAL ;
    SHAPE ABUTMENT ;
    PORT
      LAYER M4 ;
      RECT 12.896 10.032 12.920 10.056 ;
    END
  END wd_in_B[28]
  PIN wd_in_A[29]
    DIRECTION INPUT ;
    USE SIGNAL ;
    SHAPE ABUTMENT ;
    PORT
      LAYER M4 ;
      RECT 0.000 10.128 0.024 10.152 ;
    END
  END wd_in_A[29]
  PIN wd_in_B[29]
    DIRECTION INPUT ;
    USE SIGNAL ;
    SHAPE ABUTMENT ;
    PORT
      LAYER M4 ;
      RECT 12.896 10.128 12.920 10.152 ;
    END
  END wd_in_B[29]
  PIN wd_in_A[30]
    DIRECTION INPUT ;
    USE SIGNAL ;
    SHAPE ABUTMENT ;
    PORT
      LAYER M4 ;
      RECT 0.000 10.224 0.024 10.248 ;
    END
  END wd_in_A[30]
  PIN wd_in_B[30]
    DIRECTION INPUT ;
    USE SIGNAL ;
    SHAPE ABUTMENT ;
    PORT
      LAYER M4 ;
      RECT 12.896 10.224 12.920 10.248 ;
    END
  END wd_in_B[30]
  PIN wd_in_A[31]
    DIRECTION INPUT ;
    USE SIGNAL ;
    SHAPE ABUTMENT ;
    PORT
      LAYER M4 ;
      RECT 0.000 10.320 0.024 10.344 ;
    END
  END wd_in_A[31]
  PIN wd_in_B[31]
    DIRECTION INPUT ;
    USE SIGNAL ;
    SHAPE ABUTMENT ;
    PORT
      LAYER M4 ;
      RECT 12.896 10.320 12.920 10.344 ;
    END
  END wd_in_B[31]
  PIN addr_in_A[0]
    DIRECTION INPUT ;
    USE SIGNAL ;
    SHAPE ABUTMENT ;
    PORT
      LAYER M4 ;
      RECT 0.000 10.992 0.024 11.016 ;
    END
  END addr_in_A[0]
  PIN addr_in_B[0]
    DIRECTION INPUT ;
    USE SIGNAL ;
    SHAPE ABUTMENT ;
    PORT
      LAYER M4 ;
      RECT 12.896 10.992 12.920 11.016 ;
    END
  END addr_in_B[0]
  PIN addr_in_A[1]
    DIRECTION INPUT ;
    USE SIGNAL ;
    SHAPE ABUTMENT ;
    PORT
      LAYER M4 ;
      RECT 0.000 11.088 0.024 11.112 ;
    END
  END addr_in_A[1]
  PIN addr_in_B[1]
    DIRECTION INPUT ;
    USE SIGNAL ;
    SHAPE ABUTMENT ;
    PORT
      LAYER M4 ;
      RECT 12.896 11.088 12.920 11.112 ;
    END
  END addr_in_B[1]
  PIN addr_in_A[2]
    DIRECTION INPUT ;
    USE SIGNAL ;
    SHAPE ABUTMENT ;
    PORT
      LAYER M4 ;
      RECT 0.000 11.184 0.024 11.208 ;
    END
  END addr_in_A[2]
  PIN addr_in_B[2]
    DIRECTION INPUT ;
    USE SIGNAL ;
    SHAPE ABUTMENT ;
    PORT
      LAYER M4 ;
      RECT 12.896 11.184 12.920 11.208 ;
    END
  END addr_in_B[2]
  PIN addr_in_A[3]
    DIRECTION INPUT ;
    USE SIGNAL ;
    SHAPE ABUTMENT ;
    PORT
      LAYER M4 ;
      RECT 0.000 11.280 0.024 11.304 ;
    END
  END addr_in_A[3]
  PIN addr_in_B[3]
    DIRECTION INPUT ;
    USE SIGNAL ;
    SHAPE ABUTMENT ;
    PORT
      LAYER M4 ;
      RECT 12.896 11.280 12.920 11.304 ;
    END
  END addr_in_B[3]
  PIN addr_in_A[4]
    DIRECTION INPUT ;
    USE SIGNAL ;
    SHAPE ABUTMENT ;
    PORT
      LAYER M4 ;
      RECT 0.000 11.376 0.024 11.400 ;
    END
  END addr_in_A[4]
  PIN addr_in_B[4]
    DIRECTION INPUT ;
    USE SIGNAL ;
    SHAPE ABUTMENT ;
    PORT
      LAYER M4 ;
      RECT 12.896 11.376 12.920 11.400 ;
    END
  END addr_in_B[4]
  PIN addr_in_A[5]
    DIRECTION INPUT ;
    USE SIGNAL ;
    SHAPE ABUTMENT ;
    PORT
      LAYER M4 ;
      RECT 0.000 11.472 0.024 11.496 ;
    END
  END addr_in_A[5]
  PIN addr_in_B[5]
    DIRECTION INPUT ;
    USE SIGNAL ;
    SHAPE ABUTMENT ;
    PORT
      LAYER M4 ;
      RECT 12.896 11.472 12.920 11.496 ;
    END
  END addr_in_B[5]
  PIN we_in_A
    DIRECTION INPUT ;
    USE SIGNAL ;
    SHAPE ABUTMENT ;
    PORT
      LAYER M4 ;
      RECT 0.000 12.144 0.024 12.168 ;
    END
  END we_in_A
  PIN we_in_B
    DIRECTION INPUT ;
    USE SIGNAL ;
    SHAPE ABUTMENT ;
    PORT
      LAYER M4 ;
      RECT 12.896 12.144 12.920 12.168 ;
    END
  END we_in_B
  PIN ce_in_A
    DIRECTION INPUT ;
    USE SIGNAL ;
    SHAPE ABUTMENT ;
    PORT
      LAYER M4 ;
      RECT 0.000 12.240 0.024 12.264 ;
    END
  END ce_in_A
  PIN clk_A
    DIRECTION INPUT ;
    USE SIGNAL ;
    SHAPE ABUTMENT ;
    PORT
      LAYER M4 ;
      RECT 0.000 12.336 0.024 12.360 ;
    END
  END clk_A
  PIN ce_in_B
    DIRECTION INPUT ;
    USE SIGNAL ;
    SHAPE ABUTMENT ;
    PORT
      LAYER M4 ;
      RECT 0.000 12.432 0.024 12.456 ;
    END
  END ce_in_B
  PIN clk_B
    DIRECTION INPUT ;
    USE SIGNAL ;
    SHAPE ABUTMENT ;
    PORT
      LAYER M4 ;
      RECT 0.000 12.528 0.024 12.552 ;
    END
  END clk_B
  PIN VSS
    DIRECTION INOUT ;
    USE GROUND ;
    PORT
      LAYER M4 ;
      RECT 0.048 0.000 12.872 0.096 ;
      RECT 0.048 0.768 12.872 0.864 ;
      RECT 0.048 1.536 12.872 1.632 ;
      RECT 0.048 2.304 12.872 2.400 ;
      RECT 0.048 3.072 12.872 3.168 ;
      RECT 0.048 3.840 12.872 3.936 ;
      RECT 0.048 4.608 12.872 4.704 ;
      RECT 0.048 5.376 12.872 5.472 ;
      RECT 0.048 6.144 12.872 6.240 ;
      RECT 0.048 6.912 12.872 7.008 ;
      RECT 0.048 7.680 12.872 7.776 ;
      RECT 0.048 8.448 12.872 8.544 ;
      RECT 0.048 9.216 12.872 9.312 ;
      RECT 0.048 9.984 12.872 10.080 ;
      RECT 0.048 10.752 12.872 10.848 ;
      RECT 0.048 11.520 12.872 11.616 ;
      RECT 0.048 12.288 12.872 12.384 ;
    END
  END VSS
  PIN VDD
    DIRECTION INOUT ;
    USE POWER ;
    PORT
      LAYER M4 ;
      RECT 0.048 0.384 12.872 0.480 ;
      RECT 0.048 1.152 12.872 1.248 ;
      RECT 0.048 1.920 12.872 2.016 ;
      RECT 0.048 2.688 12.872 2.784 ;
      RECT 0.048 3.456 12.872 3.552 ;
      RECT 0.048 4.224 12.872 4.320 ;
      RECT 0.048 4.992 12.872 5.088 ;
      RECT 0.048 5.760 12.872 5.856 ;
      RECT 0.048 6.528 12.872 6.624 ;
      RECT 0.048 7.296 12.872 7.392 ;
      RECT 0.048 8.064 12.872 8.160 ;
      RECT 0.048 8.832 12.872 8.928 ;
      RECT 0.048 9.600 12.872 9.696 ;
      RECT 0.048 10.368 12.872 10.464 ;
      RECT 0.048 11.136 12.872 11.232 ;
      RECT 0.048 11.904 12.872 12.000 ;
    END
  END VDD
  OBS
    LAYER M1 ;
    RECT 0 0 12.920 12.600 ;
    LAYER M2 ;
    RECT 0 0 12.920 12.600 ;
    LAYER M3 ;
    RECT 0 0 12.920 12.600 ;
    LAYER M4 ;
    RECT 0 0 12.920 12.600 ;
  END
END fakeram7_tdp_64x32

END LIBRARY
